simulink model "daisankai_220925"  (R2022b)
settings: Solver=VariableStepAuto  StartTime=0.0  StopTime=40  RelTol=1e-3
PreLoadFcn:
  | Kp=1
  | Ki=1

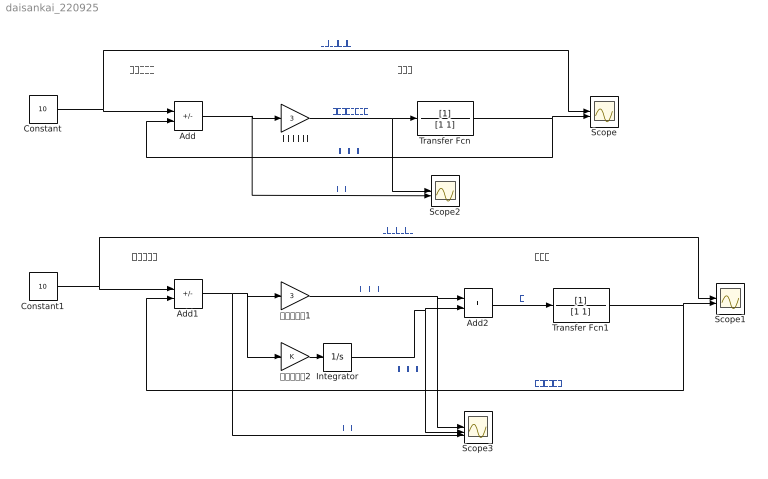
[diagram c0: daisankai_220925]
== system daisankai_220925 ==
  note: プログラム
  note: 乗り物
  note: 乗り物
  note: プログラム
  Add : Sum  Inputs=+-
  Add1 : Sum  Inputs=+-
  Add2 : Sum
  Constant : Constant  Value=10
  Constant1 : Constant  Value=10
  Integrator : Integrator
  Scope : Scope  NumInputPorts=2
  Scope1 : Scope  NumInputPorts=2
  Scope2 : Scope  NumInputPorts=2
  Scope3 : Scope  NumInputPorts=3
  Transfer Fcn : TransferFcn  Denominator=[1 1]
  Transfer Fcn1 : TransferFcn  Denominator=[1 1]
  比例ゲイン : Gain  Gain=3
  比例ゲイン1 : Gain  Gain=3
  比例ゲイン2 : Gain
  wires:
  Constant/1 -> Scope/1, Add/1  "ロボットの速度"
  Add/1 -> Scope2/2, 比例ゲイン/1  "偏差"
  比例ゲイン/1 -> Scope2/1, Transfer Fcn/1  "比例項の出力、力"
  Transfer Fcn/1 -> Add/2, Scope/2  "乗り物の速度"
  Transfer Fcn1/1 -> Add1/2, Scope1/2  "乗り物の速度"
  Add1/1 -> Scope3/3, 比例ゲイン2/1, 比例ゲイン1/1  "偏差"
  比例ゲイン1/1 -> Scope3/1, Add2/1  "比例項の出力"
  Constant1/1 -> Scope1/1, Add1/1  "ロボットの速度"
  比例ゲイン2/1 -> Integrator/1
  Add2/1 -> Transfer Fcn1/1  "力"
  Integrator/1 -> Scope3/2, Add2/2  "積分項の出力"
